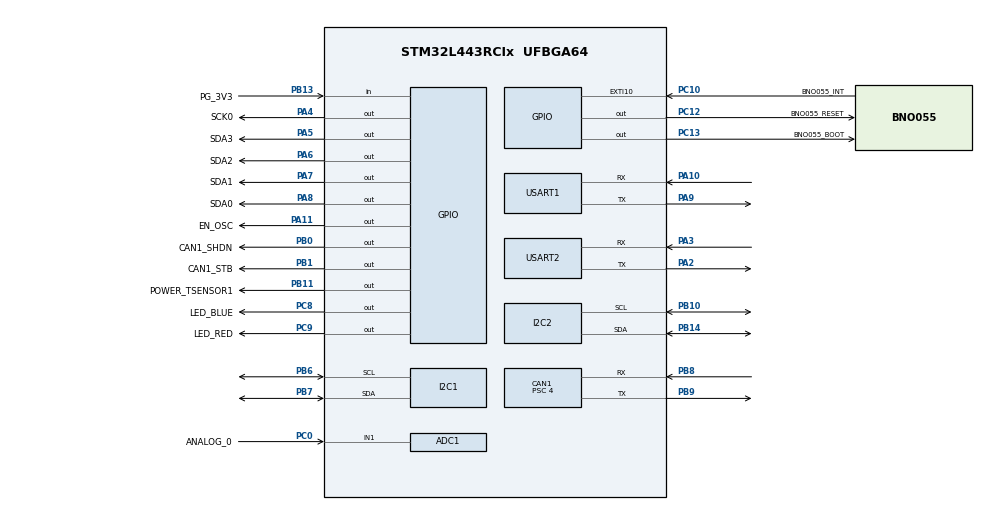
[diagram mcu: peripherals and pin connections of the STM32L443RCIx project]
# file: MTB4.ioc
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ADC1.Channel-0\#ChannelRegularConversion=ADC_CHANNEL_1
ADC1.ClockPrescaler=ADC_CLOCK_ASYNC_DIV1
ADC1.ContinuousConvMode=DISABLE
ADC1.DMAContinuousRequests=DISABLE
ADC1.DataAlign=ADC_DATAALIGN_RIGHT
ADC1.DiscontinuousConvMode=DISABLE
ADC1.EOCSelection=ADC_EOC_SINGLE_CONV
ADC1.EnableAnalogWatchDog1=false
ADC1.EnableAnalogWatchDog2=false
ADC1.EnableAnalogWatchDog3=false
ADC1.EnableInjectedConversion=DISABLE
ADC1.EnableRegularConversion=ENABLE
ADC1.ExternalTrigConv=ADC_SOFTWARE_START
ADC1.ExternalTrigConvEdge=ADC_EXTERNALTRIGCONVEDGE_NONE
ADC1.LowPowerAutoWait=DISABLE
ADC1.NbrOfConversion=1
ADC1.NbrOfConversionFlag=1
ADC1.OffsetNumber-0\#ChannelRegularConversion=ADC_OFFSET_NONE
ADC1.Overrun=ADC_OVR_DATA_PRESERVED
ADC1.OversamplingMode=DISABLE
ADC1.Rank-0\#ChannelRegularConversion=1
ADC1.Resolution=ADC_RESOLUTION_12B
ADC1.SamplingTime-0\#ChannelRegularConversion=ADC_SAMPLETIME_2CYCLES_5
ADC1.ScanConvMode=ADC_SCAN_DISABLE
ADC1.master=1
CAN1.ABOM=ENABLE
CAN1.AWUM=ENABLE
CAN1.BS1=CAN_BS1_5TQ
CAN1.BS2=CAN_BS2_4TQ
CAN1.CalculateBaudRate=1000000
CAN1.CalculateTimeBit=1000
CAN1.CalculateTimeQuantum=100.0
CAN1.Mode=CAN_MODE_NORMAL
CAN1.Prescaler=4
CAN1.SJW=CAN_SJW_1TQ
Dma.I2C1_RX.3.Direction=DMA_PERIPH_TO_MEMORY
Dma.I2C1_RX.3.Instance=DMA1_Channel7
Dma.I2C1_RX.3.MemDataAlignment=DMA_MDATAALIGN_BYTE
Dma.I2C1_RX.3.MemInc=DMA_MINC_ENABLE
Dma.I2C1_RX.3.Mode=DMA_NORMAL
Dma.I2C1_RX.3.PeriphDataAlignment=DMA_PDATAALIGN_BYTE
Dma.I2C1_RX.3.PeriphInc=DMA_PINC_DISABLE
Dma.I2C1_RX.3.Priority=DMA_PRIORITY_LOW
Dma.I2C1_TX.2.Direction=DMA_MEMORY_TO_PERIPH
Dma.I2C1_TX.2.Instance=DMA1_Channel6
Dma.I2C1_TX.2.MemDataAlignment=DMA_MDATAALIGN_BYTE
Dma.I2C1_TX.2.MemInc=DMA_MINC_ENABLE
Dma.I2C1_TX.2.Mode=DMA_NORMAL
Dma.I2C1_TX.2.PeriphDataAlignment=DMA_PDATAALIGN_BYTE
Dma.I2C1_TX.2.PeriphInc=DMA_PINC_DISABLE
Dma.I2C1_TX.2.Priority=DMA_PRIORITY_LOW
Dma.I2C2_RX.1.Direction=DMA_PERIPH_TO_MEMORY
Dma.I2C2_RX.1.Instance=DMA1_Channel5
Dma.I2C2_RX.1.MemDataAlignment=DMA_MDATAALIGN_BYTE
Dma.I2C2_RX.1.MemInc=DMA_MINC_ENABLE
Dma.I2C2_RX.1.Mode=DMA_NORMAL
Dma.I2C2_RX.1.PeriphDataAlignment=DMA_PDATAALIGN_BYTE
Dma.I2C2_RX.1.PeriphInc=DMA_PINC_DISABLE
Dma.I2C2_RX.1.Priority=DMA_PRIORITY_LOW
Dma.I2C2_TX.0.Direction=DMA_MEMORY_TO_PERIPH
Dma.I2C2_TX.0.Instance=DMA1_Channel4
Dma.I2C2_TX.0.MemDataAlignment=DMA_MDATAALIGN_BYTE
Dma.I2C2_TX.0.MemInc=DMA_MINC_ENABLE
Dma.I2C2_TX.0.Mode=DMA_NORMAL
Dma.I2C2_TX.0.PeriphDataAlignment=DMA_PDATAALIGN_BYTE
Dma.I2C2_TX.0.PeriphInc=DMA_PINC_DISABLE
Dma.I2C2_TX.0.Priority=DMA_PRIORITY_LOW
Dma.Request0=I2C2_TX
Dma.Request1=I2C2_RX
Dma.Request2=I2C1_TX
Dma.Request3=I2C1_RX
Dma.Request4=USART1_TX
Dma.Request5=USART1_RX
Dma.USART1_RX.5.Direction=DMA_PERIPH_TO_MEMORY
Dma.USART1_RX.5.Instance=DMA2_Channel7
Dma.USART1_RX.5.MemDataAlignment=DMA_MDATAALIGN_BYTE
Dma.USART1_RX.5.MemInc=DMA_MINC_ENABLE
Dma.USART1_RX.5.Mode=DMA_NORMAL
Dma.USART1_RX.5.PeriphDataAlignment=DMA_PDATAALIGN_BYTE
Dma.USART1_RX.5.PeriphInc=DMA_PINC_DISABLE
Dma.USART1_RX.5.Priority=DMA_PRIORITY_LOW
Dma.USART1_TX.4.Direction=DMA_MEMORY_TO_PERIPH
Dma.USART1_TX.4.Instance=DMA2_Channel6
Dma.USART1_TX.4.MemDataAlignment=DMA_MDATAALIGN_BYTE
Dma.USART1_TX.4.MemInc=DMA_MINC_ENABLE
Dma.USART1_TX.4.Mode=DMA_NORMAL
Dma.USART1_TX.4.PeriphDataAlignment=DMA_PDATAALIGN_BYTE
Dma.USART1_TX.4.PeriphInc=DMA_PINC_DISABLE
Dma.USART1_TX.4.Priority=DMA_PRIORITY_LOW
I2C1.NoStretchMode=I2C_NOSTRETCH_ENABLE
I2C1.OwnAddress=0
I2C1.Speed=100
I2C1.Timing=0x00909BEB
I2C2.Speed=100
I2C2.Timing=0x00909BEB
Mcu.Family=STM32L4
Mcu.Name=STM32L443RCIx
Mcu.Package=UFBGA64
NVIC.CAN1_RX0_IRQn=true\:0\:0\:false\:false\:true\:true\:true\:true
NVIC.CAN1_TX_IRQn=true\:0\:0\:false\:false\:true\:true\:true\:true
NVIC.DMA1_Channel4_IRQn=true\:0\:0\:false\:false\:true\:true\:true\:true
NVIC.DMA1_Channel5_IRQn=true\:0\:0\:false\:false\:true\:true\:true\:true
NVIC.DMA1_Channel6_IRQn=true\:0\:0\:false\:false\:true\:true\:true\:true
NVIC.DMA1_Channel7_IRQn=true\:0\:0\:false\:false\:true\:true\:true\:true
NVIC.DMA2_Channel6_IRQn=true\:0\:0\:false\:false\:true\:true\:true\:true
NVIC.DMA2_Channel7_IRQn=true\:0\:0\:false\:false\:true\:true\:true\:true
NVIC.I2C1_ER_IRQn=true\:0\:0\:false\:false\:true\:true\:true\:true
NVIC.I2C1_EV_IRQn=true\:0\:0\:false\:false\:true\:true\:true\:true
NVIC.I2C2_ER_IRQn=true\:0\:0\:false\:false\:true\:true\:true\:true
NVIC.I2C2_EV_IRQn=true\:0\:0\:false\:false\:true\:true\:true\:true
NVIC.PriorityGroup=NVIC_PRIORITYGROUP_4
NVIC.TIM6_DAC_IRQn=true\:0\:0\:false\:false\:true\:true\:true\:true
NVIC.USART1_IRQn=true\:0\:0\:false\:false\:true\:true\:true\:true
NVIC.USART2_IRQn=true\:0\:0\:false\:false\:true\:true\:true\:true
PA10.Mode=Asynchronous
PA10.Signal=USART1_RX
PA11.GPIO_Label=EN_OSC
PA11.GPIO_PuPd=GPIO_PULLUP
PA11.PinState=GPIO_PIN_SET
PA11.Signal=GPIO_Output
PA13\ (JTMS-SWDIO).Mode=Serial_Wire
PA13\ (JTMS-SWDIO).Signal=SYS_JTMS-SWDIO
PA14\ (JTCK-SWCLK).Mode=Serial_Wire
PA14\ (JTCK-SWCLK).Signal=SYS_JTCK-SWCLK
PA2.Mode=Asynchronous
PA2.Signal=USART2_TX
PA3.Mode=Asynchronous
PA3.Signal=USART2_RX
PA4.GPIO_Label=SCK0
PA4.Signal=GPIO_Output
PA5.GPIO_Label=SDA3
PA5.Signal=GPIO_Output
PA6.GPIO_Label=SDA2
PA6.Signal=GPIO_Output
PA7.GPIO_Label=SDA1
PA7.Signal=GPIO_Output
PA8.GPIO_Label=SDA0
PA8.Signal=GPIO_Output
PA9.Mode=Asynchronous
PA9.Signal=USART1_TX
PB0.GPIO_Label=CAN1_SHDN
PB0.Signal=GPIO_Output
PB1.GPIO_Label=CAN1_STB
PB1.Signal=GPIO_Output
PB10.GPIO_Pu=GPIO_PULLUP
PB10.Mode=I2C
PB10.Signal=I2C2_SCL
PB11.GPIO_Label=POWER_TSENSOR1
PB11.Signal=GPIO_Output
PB13.GPIO_Label=PG_3V3
PB13.Signal=GPIO_Input
PB14.GPIO_Pu=GPIO_PULLUP
PB14.Mode=I2C
PB14.Signal=I2C2_SDA
PB6.GPIO_Pu=GPIO_PULLUP
PB6.Mode=I2C
PB6.Signal=I2C1_SCL
PB7.GPIO_Pu=GPIO_PULLUP
PB7.Mode=I2C
PB7.Signal=I2C1_SDA
PB8.Mode=CAN_Activate
PB8.Signal=CAN1_RX
PB9.Mode=CAN_Activate
PB9.Signal=CAN1_TX
PC0.GPIO_Label=ANALOG_0
PC0.Signal=ADCx_IN1
PC10.GPIO_Label=BNO055_INT
PC10.Signal=GPXTI10
PC12.GPIO_Label=BNO055_RESET
PC12.Signal=GPIO_Output
PC13.GPIO_Label=BNO055_BOOT
PC13.Signal=GPIO_Output
PC8.GPIO_Label=LED_BLUE
PC8.Signal=GPIO_Output
PC9.GPIO_Label=LED_RED
PC9.Signal=GPIO_Output
PH0-OSC_IN\ (PH0).Mode=HSE-External-Clock-Source
PH0-OSC_IN\ (PH0).Signal=RCC_OSC_IN
ProjectManager.HeapSize=0x200
ProjectManager.StackSize=0x400
ProjectManager.TargetToolchain=MDK-ARM V5
RCC.ADCFreq_Value=40000000
RCC.AHBFreq_Value=40000000
RCC.APB1Freq_Value=40000000
RCC.APB1TimFreq_Value=40000000
RCC.APB2Freq_Value=40000000
RCC.APB2TimFreq_Value=40000000
RCC.CK48CLockSelection=RCC_USBCLKSOURCE_HSI48
RCC.CortexFreq_Value=40000000
RCC.EnbaleCSS=true
RCC.HCLKFreq_Value=40000000
RCC.HSE_VALUE=10000000
RCC.HSI48_VALUE=48000000
RCC.HSI_VALUE=16000000
RCC.LSE_VALUE=32768
RCC.MSI_VALUE=4000000
RCC.PLLM=2
RCC.PLLN=16
RCC.PLLSAI1N=16
RCC.PLLSourceVirtual=RCC_PLLSOURCE_HSE
RCC.SYSCLKFreq_VALUE=40000000
RCC.SYSCLKSource=RCC_SYSCLKSOURCE_PLLCLK
RCC.USBFreq_Value=48000000
RCC.VCOOutputFreq_Value=80000000
SH.ADCx_IN1.0=ADC1_IN1,IN1-Single-Ended
TIM6.Period=1
TIM6.Prescaler=1000
USART1.VirtualMode-Asynchronous=VM_ASYNC
USART1.WordLength=WORDLENGTH_8B
USART2.VirtualMode-Asynchronous=VM_ASYNC
USART2.WordLength=WORDLENGTH_8B
VP_RNG_VS_RNG.Mode=RNG_Activate
VP_TIM6_VS_ClockSourceINT.Mode=Enable_Timer
board=MTB4

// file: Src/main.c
/* USER CODE BEGIN Header */
/**
  ******************************************************************************
  * @file           : main.c
  * @brief          : Main program body
  ******************************************************************************
  ** This notice applies to any and all portions of this file
  * that are not between comment pairs USER CODE BEGIN and
  * USER CODE END. Other portions of this file, whether
  * inserted by the user or by software development tools
  * are owned by their respective copyright owners.
  *
  * COPYRIGHT(c) 2019 STMicroelectronics
  *
  * Redistribution and use in source and binary forms, with or without modification,
  * are permitted provided that the following conditions are met:
  *   1. Redistributions of source code must retain the above copyright notice,
  *      this list of conditions and the following disclaimer.
  *   2. Redistributions in binary form must reproduce the above copyright notice,
  *      this list of conditions and the following disclaimer in the documentation
  *      and/or other materials provided with the distribution.
  *   3. Neither the name of STMicroelectronics nor the names of its contributors
  *      may be used to endorse or promote products derived from this software
  *      without specific prior written permission.
  *
  * THIS SOFTWARE IS PROVIDED BY THE COPYRIGHT HOLDERS AND CONTRIBUTORS "AS IS"
  * AND ANY EXPRESS OR IMPLIED WARRANTIES, INCLUDING, BUT NOT LIMITED TO, THE
  * IMPLIED WARRANTIES OF MERCHANTABILITY AND FITNESS FOR A PARTICULAR PURPOSE ARE
  * DISCLAIMED. IN NO EVENT SHALL THE COPYRIGHT HOLDER OR CONTRIBUTORS BE LIABLE
  * FOR ANY DIRECT, INDIRECT, INCIDENTAL, SPECIAL, EXEMPLARY, OR CONSEQUENTIAL
  * DAMAGES (INCLUDING, BUT NOT LIMITED TO, PROCUREMENT OF SUBSTITUTE GOODS OR
  * SERVICES; LOSS OF USE, DATA, OR PROFITS; OR BUSINESS INTERRUPTION) HOWEVER
  * CAUSED AND ON ANY THEORY OF LIABILITY, WHETHER IN CONTRACT, STRICT LIABILITY,
  * OR TORT (INCLUDING NEGLIGENCE OR OTHERWISE) ARISING IN ANY WAY OUT OF THE USE
  * OF THIS SOFTWARE, EVEN IF ADVISED OF THE POSSIBILITY OF SUCH DAMAGE.
  *
  ******************************************************************************
  */
/* USER CODE END Header */

#include "main.h"
#include "adc.h"
#include "can.h"
#include "dma.h"
#include "i2c.h"
#include "rng.h"
#include "tim.h"
#include "usart.h"
#include "gpio.h"

/* USER CODE BEGIN Includes */
#include "can_utility.h"
#include "Si705x.h"
#include "BNO055.h"
//#include "EOsensor_BNO055.h"
#include "AD7147.h"
#include "AD7147RegMap.h"
#include "I2C_Multi_SDA.h"

/* USER CODE END Includes */

/* USER CODE BEGIN PV */
/* Private variables ---------------------------------------------------------*/

// ----------------------------------------------------------------------------
// Firmware Version
// ----------------------------------------------------------------------------
char Firmware_vers = 0;
char Revision_vers = 0;
char Build_number  = 0;

uint8_t can_message = 0;
uint8_t count = 0;

uint16_t Temperature_code;
uint32_t Temperature_board;
uint8_t Temp_int;
uint8_t Temp_dec;

uint8_t text[5] = {0};
uint8_t UART_Rx_buffer[5];

unsigned int channel=0;
extern unsigned int AD7147Registers[2][16][12]; // il primo campo rappresenta il numero dei canali
extern unsigned int CapOffset[2][16][12];       // il primo campo rappresenta il numero dei canali
extern error_cap err[16];
extern unsigned char AD7147_ADD[4];

extern triangle_cfg_t triangle_cfg_list[16];
unsigned char TEMP_COMPENSATION=1;              // if 1 means internal temperature drift compensation
unsigned int taxel[2][16][12];               // il primo campo rappresenta il numero dei canali
int16_t skin_value[2][16];                      // il primo campo rappresenta il numero dei canali
int TOUCH_THREASHOLD=(2450-140);
int SKIN_UPPER_THRESHOLD=2480;
int ERROR_COUNTER=0;

int8_t SKIN_STATE_2T=-1;    // bottom 2 triangles skin state
int8_t SKIN_STATE_10T=-1;   // upper 10 triangles skin state
int8_t SKIN_STATE=-1;
int8_t SKIN_OVER_THRESHOLD=0;
uint8_t WAVEFORM=1;

int16_t triangle[2][16] = {0};
int16_t triangle_old[2][16] = {0};

/* USER CODE END PV */

void SystemClock_Config(void);
/* USER CODE BEGIN PFP */
/* Private function prototypes -----------------------------------------------*/
void LED_Init(void);
void TIMER_Init(void);
void TEMPERATURE(void);
void BNO055(void);
void BNO055_UART(void);

void FillMessages8bit(unsigned char Channel,unsigned char triangleN);
void UpdateTouchMap(void);
void TouchMapHistoryCheck(void);
void SkinRawData(void);

/* USER CODE END PFP */

int main(void)
{

  /* MCU Configuration--------------------------------------------------------*/

  /* Reset of all peripherals, Initializes the Flash interface and the Systick. */
  HAL_Init();

  /* Configure the system clock */
  SystemClock_Config();

  /* Initialize all configured peripherals */
  MX_GPIO_Init();
  MX_DMA_Init();
  MX_TIM6_Init();
  MX_CAN1_Init();
  MX_USART1_UART_Init();
  MX_I2C1_Init();
  MX_I2C2_Init();
  MX_USART2_UART_Init();
  MX_ADC1_Init();
  MX_RNG_Init();
  /* USER CODE BEGIN 2 */
  TIMER_Init();
  LED_Init();
  CAN_Config();
  Si705x_init();
  BNO055_init();

  /* USER CODE END 2 */

  /* Infinite loop */
  /* USER CODE BEGIN WHILE */
  //HAL_UART_Receive_DMA(&huart1,(uint8_t*)UART_Rx_buffer, sizeof(UART_Rx_buffer));

  /*##-2- Start the Reception process and enable reception interrupt #########*/
  if (HAL_CAN_Receive_IT(&hcan1, CAN_FIFO0) != HAL_OK)
  {
    /* Reception Error */
    Error_Handler();
  }

  while(1)
  {
    //CANBUS();
    TEMPERATURE();
    BNO055();
    //BNO055_UART();

    HAL_Delay(1000);
    text[0] = Temperature_board>>8;
    text[1] = Temperature_board;
    //HAL_UART_Transmit_DMA(&huart1, (uint8_t*)text, sizeof(text));
    //HAL_UART_Transmit(&huart1, (uint8_t*)text, 5,100);

    /* USER CODE END WHILE */

  }
}

void SystemClock_Config(void)
{
  RCC_OscInitTypeDef RCC_OscInitStruct = {0};
  RCC_ClkInitTypeDef RCC_ClkInitStruct = {0};
  RCC_PeriphCLKInitTypeDef PeriphClkInit = {0};

  /**Initializes the CPU, AHB and APB busses clocks
  */
  RCC_OscInitStruct.OscillatorType = RCC_OSCILLATORTYPE_HSI48|RCC_OSCILLATORTYPE_HSI;
  RCC_OscInitStruct.HSIState = RCC_HSI_ON;
  RCC_OscInitStruct.HSI48State = RCC_HSI48_ON;
  RCC_OscInitStruct.HSICalibrationValue = RCC_HSICALIBRATION_DEFAULT;
  RCC_OscInitStruct.PLL.PLLState = RCC_PLL_NONE;
  if (HAL_RCC_OscConfig(&RCC_OscInitStruct) != HAL_OK)
  {
    Error_Handler();
  }
  /**Initializes the CPU, AHB and APB busses clocks
  */
  RCC_ClkInitStruct.ClockType = RCC_CLOCKTYPE_HCLK|RCC_CLOCKTYPE_SYSCLK
                              |RCC_CLOCKTYPE_PCLK1|RCC_CLOCKTYPE_PCLK2;
  RCC_ClkInitStruct.SYSCLKSource = RCC_SYSCLKSOURCE_HSI;
  RCC_ClkInitStruct.AHBCLKDivider = RCC_SYSCLK_DIV1;
  RCC_ClkInitStruct.APB1CLKDivider = RCC_HCLK_DIV1;
  RCC_ClkInitStruct.APB2CLKDivider = RCC_HCLK_DIV1;

  if (HAL_RCC_ClockConfig(&RCC_ClkInitStruct, FLASH_LATENCY_0) != HAL_OK)
  {
    Error_Handler();
  }
  PeriphClkInit.PeriphClockSelection = RCC_PERIPHCLK_USART1|RCC_PERIPHCLK_USART2
                              |RCC_PERIPHCLK_I2C1|RCC_PERIPHCLK_I2C2
                              |RCC_PERIPHCLK_RNG|RCC_PERIPHCLK_ADC;
  PeriphClkInit.Usart1ClockSelection = RCC_USART1CLKSOURCE_PCLK2;
  PeriphClkInit.Usart2ClockSelection = RCC_USART2CLKSOURCE_PCLK1;
  PeriphClkInit.I2c1ClockSelection = RCC_I2C1CLKSOURCE_PCLK1;
  PeriphClkInit.I2c2ClockSelection = RCC_I2C2CLKSOURCE_PCLK1;
  PeriphClkInit.AdcClockSelection = RCC_ADCCLKSOURCE_PLLSAI1;
  PeriphClkInit.RngClockSelection = RCC_RNGCLKSOURCE_HSI48;
  PeriphClkInit.PLLSAI1.PLLSAI1Source = RCC_PLLSOURCE_HSI;
  PeriphClkInit.PLLSAI1.PLLSAI1M = 1;
  PeriphClkInit.PLLSAI1.PLLSAI1N = 8;
  PeriphClkInit.PLLSAI1.PLLSAI1P = RCC_PLLP_DIV7;
  PeriphClkInit.PLLSAI1.PLLSAI1Q = RCC_PLLQ_DIV2;
  PeriphClkInit.PLLSAI1.PLLSAI1R = RCC_PLLR_DIV2;
  PeriphClkInit.PLLSAI1.PLLSAI1ClockOut = RCC_PLLSAI1_ADC1CLK;
  if (HAL_RCCEx_PeriphCLKConfig(&PeriphClkInit) != HAL_OK)
  {
    Error_Handler();
  }
  /**Configure the main internal regulator output voltage
  */
  if (HAL_PWREx_ControlVoltageScaling(PWR_REGULATOR_VOLTAGE_SCALE1) != HAL_OK)
  {
    Error_Handler();
  }
}

/* USER CODE BEGIN 4 */
void HAL_SYSTICK_Callback(void)
{
	static uint32_t count=0;
	if(count==1000){
		//HAL_GPIO_TogglePin(LED_BLUE_GPIO_Port, LED_BLUE_Pin);
		count=0;
	}
	count++;
}

// -----------------------------------------------------------------------------------------------------------------------------
// Timers initialization
// -----------------------------------------------------------------------------------------------------------------------------
void TIMER_Init(void){
  //HAL_TIM_Base_Start_IT(&htim6);    // 100us
  //HAL_TIM_IRQHandler(&htim6);
}

// -----------------------------------------------------------------------------------------------------------------------------
// LEDs initialization
// -----------------------------------------------------------------------------------------------------------------------------
void LED_Init(void){
  HAL_GPIO_WritePin(LED_RED_GPIO_Port, LED_RED_Pin, GPIO_PIN_SET);
  HAL_GPIO_WritePin(LED_BLUE_GPIO_Port, LED_BLUE_Pin, GPIO_PIN_SET);
}

// -----------------------------------------------------------------------------------------------------------------------------
// CAN messages management
// -----------------------------------------------------------------------------------------------------------------------------
void CANBUS(void){
	switch(can_message){
    case 0x00:
    {
      hcan1.pTxMsg->StdId   = 0x621;              // Polling
      hcan1.pTxMsg->Data[0] = 0xFF;               // Firmware version message
      hcan1.pTxMsg->Data[1] = 0x02;               // Board type
      hcan1.pTxMsg->Data[2] = Firmware_vers;      // Firmware version
      hcan1.pTxMsg->Data[3] = Revision_vers;      // Revision version
      hcan1.pTxMsg->Data[4] = Build_number;       // Build number
      hcan1.pTxMsg->Data[5] = 0;
      hcan1.pTxMsg->Data[6] = Temperature_board>>8;
      hcan1.pTxMsg->Data[7] = Temperature_board;
      HAL_CAN_Transmit_IT(&hcan1);
      can_message = 0;
    }
    break;

    default:
    {
    }
    break;
  }
}

// -----------------------------------------------------------------------------------------------------------------------------
// Read the Sensor Temperature
// -----------------------------------------------------------------------------------------------------------------------------
void TEMPERATURE(void){
  Si705x_ReadTemperature();
}

// -----------------------------------------------------------------------------------------------------------------------------
// Read the IMU BNO055 I2C
// -----------------------------------------------------------------------------------------------------------------------------
void BNO055(void){
  BNO055_Read();
}

// -----------------------------------------------------------------------------------------------------------------------------
// Read the IMU BNO055 UART
// -----------------------------------------------------------------------------------------------------------------------------
void BNO055_UART(void){
  BNO055_UART_Read();
}

void HAL_I2C_MasterTxCpltCallback(I2C_HandleTypeDef *I2cHandle)
{
  if(I2cHandle->Instance==I2C1){
    HAL_I2C_Master_Receive_DMA(&hi2c1, (uint16_t)Si705x_I2C_ADDRESS, (uint8_t*)Si705x_I2C_RxBuffer, sizeof(Si705x_I2C_RxBuffer));
  }
  if(I2cHandle->Instance==I2C2){
    HAL_I2C_Master_Receive_DMA(&hi2c2, (uint16_t)BNO055_I2C_ADDRESS, (uint8_t*)BNO055_RxBuffer, sizeof(BNO055_RxBuffer));

  }
}

void HAL_I2C_MasterRxCpltCallback(I2C_HandleTypeDef *I2cHandle)
{
  if(I2cHandle->Instance==I2C1){
    Temperature_code = (Si705x_I2C_RxBuffer[0]<<8) + Si705x_I2C_RxBuffer[1];
    Temperature_board = ((17572*Temperature_code)/65536) - 4685;  // HEX temperature in degrees Celsius (x100)
  }
  if(I2cHandle->Instance==I2C2){

  }
}

void HAL_UART_TxCpltCallback(UART_HandleTypeDef *huart){
  HAL_GPIO_TogglePin(LED_BLUE_GPIO_Port, LED_BLUE_Pin);
  HAL_UART_Receive_DMA(&huart1,(uint8_t*)UART_Rx_buffer, sizeof(UART_Rx_buffer));
}

void HAL_UART_RxCpltCallback(UART_HandleTypeDef *huart){
  HAL_GPIO_TogglePin(LED_RED_GPIO_Port, LED_RED_Pin);
  HAL_UART_Transmit_DMA(&huart1,(uint8_t*)UART_Rx_buffer, sizeof(UART_Rx_buffer));
}

/* USER CODE END 4 */

void Error_Handler(void)
{
  while(1)
  {
  }
}

/************************ (C) COPYRIGHT STMicroelectronics *****END OF FILE****/
